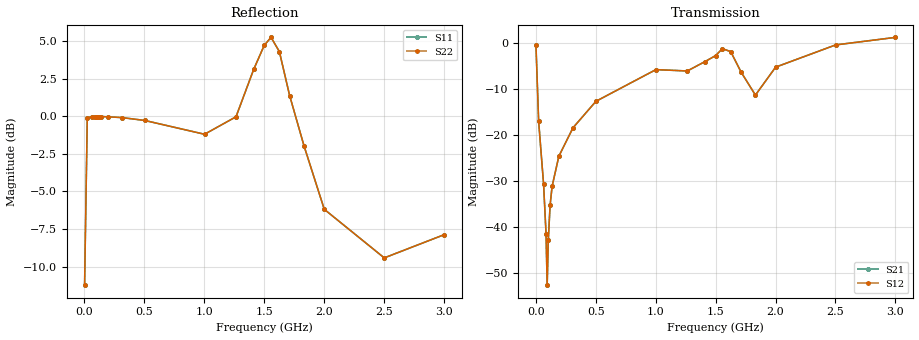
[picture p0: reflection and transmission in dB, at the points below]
!s-Parameter Generated by FASTRON Sdn. Bhd.
!FASTRON P/N : MICC-4R7X
!Keysight Technologies,E4991B,MY54100416,A.01.15
!Date: Fri Aug 28 10:26:34 2026
!Version  : Rev00 Fri Aug 28 10:26:34 2026
!Data & Calibration Information:
!PortZ  Port1:50+j0  Port2:50+j0
!When reading, reference impedance value at option line is always used.
!Remarks : This data is being provided solely for informational purposes.
!Freq	S11	S21	S12	S22
# Hz S dB R 50
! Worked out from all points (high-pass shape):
!   1601 points, 1 MHz to 3 GHz, reference 50 ohm
!   highest |S21| = 1.21 dB at 3 GHz (marker M1); lowest = -52.6 dB at 94.72 MHz (marker M2)
!   |S21| within 3 dB of the highest: 1.535 GHz to 1.624 GHz (89.38 MHz wide, 5.66 % of centre); 2.288 GHz to end of sweep (the widest 2 of 3)
!   lowest |S11| = -11.2 dB at 1 MHz (marker M3), VSWR 1.76, Z = 50.7 + j28.7 ohm
!   |S11| at or under -10 dB: start of sweep to 1.319 MHz
!   |S22| runs from -11.2 to 5.3 dB; largest |S21 - S12| = 0
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1000000  -11.23 72.7  -0.40 -15.9  -0.40 -15.9  -11.23 72.7
2.34925e7  -0.11 8.1  -17.02 -80.9  -17.02 -80.9  -0.11 8.1
6.472875e7  -0.02 1.7  -30.69 -84.0  -30.69 -84.0  -0.02 1.7
8.534688e7  -0.02 0.5  -41.52 -73.6  -41.52 -73.6  -0.02 0.5
9.471875e7  -0.02 0.0  -52.65 -7.6  -52.65 -7.6  -0.02 0.0
1.040906e8  -0.02 -0.4  -42.89 71.3  -42.89 71.3  -0.02 -0.4
1.190856e8  -0.02 -1.0  -35.28 81.5  -35.28 81.5  -0.02 -1.0
1.35955e8  -0.02 -1.6  -31.15 83.6  -31.15 83.6  -0.02 -1.6
1.921862e8  -0.04 -3.4  -24.63 84.2  -24.63 84.2  -0.04 -3.4
3.102719e8  -0.09 -6.9  -18.44 81.8  -18.44 81.8  -0.09 -6.9
5.014581e8  -0.28 -13.4  -12.69 75.5  -12.69 75.5  -0.28 -13.4
1.001916e9  -1.20 -30.8  -5.80 60.5  -5.80 60.5  -1.20 -30.8
1.264329e9  -0.04 -28.8  -6.09 75.1  -6.09 75.1  -0.04 -28.8
1.412404e9  3.12 -22.0  -4.04 121.4  -4.04 121.4  3.12 -22.0
1.5005e9  4.72 -4.2  -2.75 170.1  -2.75 170.1  4.72 -4.2
1.556731e9  5.24 10.8  -1.25 -156.8  -1.25 -156.8  5.24 10.8
1.626083e9  4.30 21.9  -1.88 -130.5  -1.88 -130.5  4.30 21.9
1.712304e9  1.36 24.2  -6.31 -97.9  -6.31 -97.9  1.36 24.2
1.832264e9  -1.98 11.5  -11.34 -35.9  -11.34 -35.9  -1.98 11.5
2.000958e9  -6.19 -16.0  -5.26 14.4  -5.26 14.4  -6.19 -16.0
2.501416e9  -9.42 -72.0  -0.43 19.7  -0.43 19.7  -9.42 -72.0
3e9  -7.88 -101.3  1.21 20.2  1.21 20.2  -7.88 -101.3
